VERSION 5.6 ;
BUSBITCHARS "[]" ;
DIVIDERCHAR "/" ;

PROPERTYDEFINITIONS
  PIN DB_Inherited_Net_Expr STRING ;
  LAYER LEF57_SPACING STRING ;
END PROPERTYDEFINITIONS

UNITS
  CAPACITANCE PICOFARADS 1 ;
  DATABASE MICRONS 2000 ;
END UNITS
MANUFACTURINGGRID 0.005 ;
LAYER Oxide
  TYPE MASTERSLICE ;
END Oxide

LAYER Poly
  TYPE MASTERSLICE ;
END Poly

LAYER Nhvt
  TYPE IMPLANT ;
END Nhvt

LAYER Nimp
  TYPE IMPLANT ;
  WIDTH 0.12 ;
  SPACING 0.12 ;
END Nimp

LAYER Phvt
  TYPE IMPLANT ;
END Phvt

LAYER Pimp
  TYPE IMPLANT ;
  WIDTH 0.12 ;
  SPACING 0.12 ;
  SPACING 0 LAYER Nimp ;
END Pimp

LAYER Nzvt
  TYPE IMPLANT ;
  WIDTH 0.35 ;
  SPACING 0.3 ;
END Nzvt

LAYER Nlvt
  TYPE IMPLANT ;
END Nlvt

LAYER Plvt
  TYPE IMPLANT ;
END Plvt

LAYER SiProt
  TYPE IMPLANT ;
  WIDTH 0.22 ;
  SPACING 0.22 ;
END SiProt

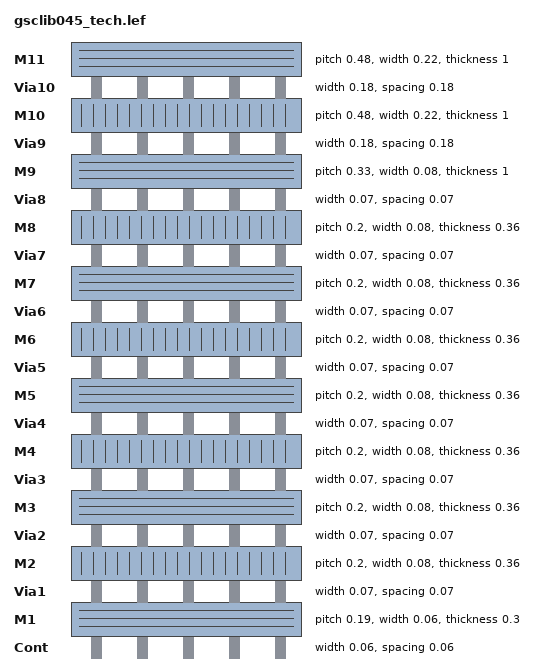
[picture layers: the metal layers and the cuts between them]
LAYER Cont
  TYPE CUT ;
  SPACING 0.06 ;
  SPACING 0.08 ADJACENTCUTS 3 WITHIN 0.1 ;
  WIDTH 0.06 ;
  ENCLOSURE BELOW 0.02 0.03 ;
  ENCLOSURE ABOVE 0 0.03 ;
  ANTENNAMODEL OXIDE1 ;
    ANTENNACUMAREARATIO 1200 ;
  DCCURRENTDENSITY AVERAGE 0.1 ;
END Cont

LAYER M1
  TYPE ROUTING ;
  DIRECTION HORIZONTAL ;
  PITCH 0.19 0.19 ;
  WIDTH 0.06 ;
  AREA 0.02 ;
  SPACINGTABLE
    PARALLELRUNLENGTH 0 0.32 0.75 1.5 2.5 3.5 
    WIDTH 0 0.06 0.06 0.06 0.06 0.06 0.06 
    WIDTH 0.1 0.06 0.1 0.1 0.1 0.1 0.1 
    WIDTH 0.75 0.06 0.1 0.25 0.25 0.25 0.25 
    WIDTH 1.5 0.06 0.1 0.25 0.45 0.45 0.45 
    WIDTH 2.5 0.06 0.1 0.25 0.45 0.75 0.75 
    WIDTH 3.5 0.06 0.1 0.25 0.45 0.75 1.25 ;
  MINENCLOSEDAREA 0.045 ;
  DIAGSPACING 0.08 ;
  DIAGMINEDGELENGTH 0.1 ;
  PROPERTY LEF57_SPACING "SPACING 0.09 ENDOFLINE 0.09 WITHIN 0.025 PARALLELEDGE 0.09 WITHIN 0.025 TWOEDGES ;" ; # OA DATAMODEL 2
  RESISTANCE RPERSQ 0.18 ;
  CAPACITANCE CPERSQDIST 0.0002 ;
  THICKNESS 0.3 ;
  EDGECAPACITANCE 0.0002 ;
  MINIMUMDENSITY 20 ;
  MAXIMUMDENSITY 65 ;
  DENSITYCHECKWINDOW 120 120 ;
  DENSITYCHECKSTEP 60 ;
  ANTENNAMODEL OXIDE1 ;
    ANTENNAAREARATIO 475 ;
  DCCURRENTDENSITY AVERAGE 2 ;
END M1

LAYER Via1
  TYPE CUT ;
  SPACING 0.07 ;
  SPACING 0.1 ADJACENTCUTS 3 WITHIN 0.11 ;
  WIDTH 0.07 ;
  ENCLOSURE BELOW 0.005 0.03 ;
  ENCLOSURE ABOVE 0.005 0.03 ;
  ANTENNAMODEL OXIDE1 ;
    ANTENNAAREARATIO 25 ;
    ANTENNACUMAREARATIO 1200 ;
  DCCURRENTDENSITY AVERAGE 0.1 ;
END Via1

LAYER M2
  TYPE ROUTING ;
  DIRECTION VERTICAL ;
  PITCH 0.2 0.2 ;
  WIDTH 0.08 ;
  AREA 0.02 ;
  SPACINGTABLE
    PARALLELRUNLENGTH 0 0.32 0.75 1.5 2.5 3.5 
    WIDTH 0 0.07 0.07 0.07 0.07 0.07 0.07 
    WIDTH 0.1 0.07 0.15 0.15 0.15 0.15 0.15 
    WIDTH 0.75 0.07 0.15 0.25 0.25 0.25 0.25 
    WIDTH 1.5 0.07 0.15 0.25 0.45 0.45 0.45 
    WIDTH 2.5 0.07 0.15 0.25 0.45 0.75 0.75 
    WIDTH 3.5 0.07 0.15 0.25 0.45 0.75 1.25 ;
  MINENCLOSEDAREA 0.055 ;
  DIAGSPACING 0.1 ;
  DIAGMINEDGELENGTH 0.1 ;
  PROPERTY LEF57_SPACING "SPACING 0.1 ENDOFLINE 0.1 WITHIN 0.035 PARALLELEDGE 0.1 WITHIN 0.035 TWOEDGES ;" ; # OA DATAMODEL 2
  RESISTANCE RPERSQ 0.17 ;
  CAPACITANCE CPERSQDIST 0.0002 ;
  THICKNESS 0.36 ;
  EDGECAPACITANCE 0.0002 ;
  MINIMUMDENSITY 20 ;
  MAXIMUMDENSITY 65 ;
  DENSITYCHECKWINDOW 120 120 ;
  DENSITYCHECKSTEP 60 ;
  ANTENNAMODEL OXIDE1 ;
    ANTENNAAREARATIO 475 ;
  DCCURRENTDENSITY AVERAGE 2 ;
END M2

LAYER Via2
  TYPE CUT ;
  SPACING 0.07 ;
  SPACING 0.1 ADJACENTCUTS 3 WITHIN 0.11 ;
  WIDTH 0.07 ;
  ENCLOSURE BELOW 0.005 0.03 ;
  ENCLOSURE ABOVE 0.005 0.03 ;
  ANTENNAMODEL OXIDE1 ;
    ANTENNAAREARATIO 25 ;
    ANTENNACUMAREARATIO 1200 ;
  DCCURRENTDENSITY AVERAGE 0.1 ;
END Via2

LAYER M3
  TYPE ROUTING ;
  DIRECTION HORIZONTAL ;
  PITCH 0.2 0.2 ;
  WIDTH 0.08 ;
  AREA 0.02 ;
  SPACINGTABLE
    PARALLELRUNLENGTH 0 0.32 0.75 1.5 2.5 3.5 
    WIDTH 0 0.07 0.07 0.07 0.07 0.07 0.07 
    WIDTH 0.1 0.07 0.15 0.15 0.15 0.15 0.15 
    WIDTH 0.75 0.07 0.15 0.25 0.25 0.25 0.25 
    WIDTH 1.5 0.07 0.15 0.25 0.45 0.45 0.45 
    WIDTH 2.5 0.07 0.15 0.25 0.45 0.75 0.75 
    WIDTH 3.5 0.07 0.15 0.25 0.45 0.75 1.25 ;
  MINENCLOSEDAREA 0.055 ;
  DIAGSPACING 0.1 ;
  DIAGMINEDGELENGTH 0.1 ;
  PROPERTY LEF57_SPACING "SPACING 0.1 ENDOFLINE 0.1 WITHIN 0.035 PARALLELEDGE 0.1 WITHIN 0.035 TWOEDGES ;" ; # OA DATAMODEL 2
  RESISTANCE RPERSQ 0.17 ;
  CAPACITANCE CPERSQDIST 0.0002 ;
  THICKNESS 0.36 ;
  EDGECAPACITANCE 0.0002 ;
  MINIMUMDENSITY 20 ;
  MAXIMUMDENSITY 65 ;
  DENSITYCHECKWINDOW 120 120 ;
  DENSITYCHECKSTEP 60 ;
  ANTENNAMODEL OXIDE1 ;
    ANTENNAAREARATIO 475 ;
  DCCURRENTDENSITY AVERAGE 2 ;
END M3

LAYER Via3
  TYPE CUT ;
  SPACING 0.07 ;
  SPACING 0.1 ADJACENTCUTS 3 WITHIN 0.11 ;
  WIDTH 0.07 ;
  ENCLOSURE BELOW 0.005 0.03 ;
  ENCLOSURE ABOVE 0.005 0.03 ;
  ANTENNAMODEL OXIDE1 ;
    ANTENNAAREARATIO 25 ;
    ANTENNACUMAREARATIO 1200 ;
  DCCURRENTDENSITY AVERAGE 0.1 ;
END Via3

LAYER M4
  TYPE ROUTING ;
  DIRECTION VERTICAL ;
  PITCH 0.2 0.2 ;
  WIDTH 0.08 ;
  AREA 0.02 ;
  SPACINGTABLE
    PARALLELRUNLENGTH 0 0.32 0.75 1.5 2.5 3.5 
    WIDTH 0 0.07 0.07 0.07 0.07 0.07 0.07 
    WIDTH 0.1 0.07 0.15 0.15 0.15 0.15 0.15 
    WIDTH 0.75 0.07 0.15 0.25 0.25 0.25 0.25 
    WIDTH 1.5 0.07 0.15 0.25 0.45 0.45 0.45 
    WIDTH 2.5 0.07 0.15 0.25 0.45 0.75 0.75 
    WIDTH 3.5 0.07 0.15 0.25 0.45 0.75 1.25 ;
  MINENCLOSEDAREA 0.055 ;
  DIAGSPACING 0.1 ;
  DIAGMINEDGELENGTH 0.1 ;
  PROPERTY LEF57_SPACING "SPACING 0.1 ENDOFLINE 0.1 WITHIN 0.035 PARALLELEDGE 0.1 WITHIN 0.035 TWOEDGES ;" ; # OA DATAMODEL 2
  RESISTANCE RPERSQ 0.17 ;
  CAPACITANCE CPERSQDIST 0.0002 ;
  THICKNESS 0.36 ;
  EDGECAPACITANCE 0.0002 ;
  MINIMUMDENSITY 20 ;
  MAXIMUMDENSITY 65 ;
  DENSITYCHECKWINDOW 120 120 ;
  DENSITYCHECKSTEP 60 ;
  ANTENNAMODEL OXIDE1 ;
    ANTENNAAREARATIO 475 ;
  DCCURRENTDENSITY AVERAGE 2 ;
END M4

LAYER Via4
  TYPE CUT ;
  SPACING 0.07 ;
  SPACING 0.1 ADJACENTCUTS 3 WITHIN 0.11 ;
  WIDTH 0.07 ;
  ENCLOSURE BELOW 0.005 0.03 ;
  ENCLOSURE ABOVE 0.005 0.03 ;
  ANTENNAMODEL OXIDE1 ;
    ANTENNAAREARATIO 25 ;
    ANTENNACUMAREARATIO 1200 ;
  DCCURRENTDENSITY AVERAGE 0.1 ;
END Via4

LAYER M5
  TYPE ROUTING ;
  DIRECTION HORIZONTAL ;
  PITCH 0.2 0.2 ;
  WIDTH 0.08 ;
  AREA 0.02 ;
  SPACINGTABLE
    PARALLELRUNLENGTH 0 0.32 0.75 1.5 2.5 3.5 
    WIDTH 0 0.07 0.07 0.07 0.07 0.07 0.07 
    WIDTH 0.1 0.07 0.15 0.15 0.15 0.15 0.15 
    WIDTH 0.75 0.07 0.15 0.25 0.25 0.25 0.25 
    WIDTH 1.5 0.07 0.15 0.25 0.45 0.45 0.45 
    WIDTH 2.5 0.07 0.15 0.25 0.45 0.75 0.75 
    WIDTH 3.5 0.07 0.15 0.25 0.45 0.75 1.25 ;
  MINENCLOSEDAREA 0.055 ;
  DIAGSPACING 0.1 ;
  DIAGMINEDGELENGTH 0.1 ;
  PROPERTY LEF57_SPACING "SPACING 0.1 ENDOFLINE 0.1 WITHIN 0.035 PARALLELEDGE 0.1 WITHIN 0.035 TWOEDGES ;" ; # OA DATAMODEL 2
  RESISTANCE RPERSQ 0.17 ;
  CAPACITANCE CPERSQDIST 0.0002 ;
  THICKNESS 0.36 ;
  EDGECAPACITANCE 0.0002 ;
  MINIMUMDENSITY 20 ;
  MAXIMUMDENSITY 65 ;
  DENSITYCHECKWINDOW 120 120 ;
  DENSITYCHECKSTEP 60 ;
  ANTENNAMODEL OXIDE1 ;
    ANTENNAAREARATIO 475 ;
  DCCURRENTDENSITY AVERAGE 2 ;
END M5

LAYER Via5
  TYPE CUT ;
  SPACING 0.07 ;
  SPACING 0.1 ADJACENTCUTS 3 WITHIN 0.11 ;
  WIDTH 0.07 ;
  ENCLOSURE BELOW 0.005 0.03 ;
  ENCLOSURE ABOVE 0.005 0.03 ;
  ANTENNAMODEL OXIDE1 ;
    ANTENNAAREARATIO 25 ;
    ANTENNACUMAREARATIO 1200 ;
  DCCURRENTDENSITY AVERAGE 0.1 ;
END Via5

LAYER M6
  TYPE ROUTING ;
  DIRECTION VERTICAL ;
  PITCH 0.2 0.2 ;
  WIDTH 0.08 ;
  AREA 0.02 ;
  SPACINGTABLE
    PARALLELRUNLENGTH 0 0.32 0.75 1.5 2.5 3.5 
    WIDTH 0 0.07 0.07 0.07 0.07 0.07 0.07 
    WIDTH 0.1 0.07 0.15 0.15 0.15 0.15 0.15 
    WIDTH 0.75 0.07 0.15 0.25 0.25 0.25 0.25 
    WIDTH 1.5 0.07 0.15 0.25 0.45 0.45 0.45 
    WIDTH 2.5 0.07 0.15 0.25 0.45 0.75 0.75 
    WIDTH 3.5 0.07 0.15 0.25 0.45 0.75 1.25 ;
  MINENCLOSEDAREA 0.055 ;
  DIAGSPACING 0.1 ;
  DIAGMINEDGELENGTH 0.1 ;
  PROPERTY LEF57_SPACING "SPACING 0.1 ENDOFLINE 0.1 WITHIN 0.035 PARALLELEDGE 0.1 WITHIN 0.035 TWOEDGES ;" ; # OA DATAMODEL 2
  RESISTANCE RPERSQ 0.17 ;
  CAPACITANCE CPERSQDIST 0.0002 ;
  THICKNESS 0.36 ;
  EDGECAPACITANCE 0.0002 ;
  MINIMUMDENSITY 20 ;
  MAXIMUMDENSITY 65 ;
  DENSITYCHECKWINDOW 120 120 ;
  DENSITYCHECKSTEP 60 ;
  ANTENNAMODEL OXIDE1 ;
    ANTENNAAREARATIO 475 ;
  DCCURRENTDENSITY AVERAGE 2 ;
END M6

LAYER Via6
  TYPE CUT ;
  SPACING 0.07 ;
  SPACING 0.1 ADJACENTCUTS 3 WITHIN 0.11 ;
  WIDTH 0.07 ;
  ENCLOSURE BELOW 0.005 0.03 ;
  ENCLOSURE ABOVE 0.005 0.03 ;
  ANTENNAMODEL OXIDE1 ;
    ANTENNAAREARATIO 25 ;
    ANTENNACUMAREARATIO 1200 ;
  DCCURRENTDENSITY AVERAGE 0.1 ;
END Via6

LAYER M7
  TYPE ROUTING ;
  DIRECTION HORIZONTAL ;
  PITCH 0.2 0.2 ;
  WIDTH 0.08 ;
  AREA 0.02 ;
  SPACINGTABLE
    PARALLELRUNLENGTH 0 0.32 0.75 1.5 2.5 3.5 
    WIDTH 0 0.07 0.07 0.07 0.07 0.07 0.07 
    WIDTH 0.1 0.07 0.15 0.15 0.15 0.15 0.15 
    WIDTH 0.75 0.07 0.15 0.25 0.25 0.25 0.25 
    WIDTH 1.5 0.07 0.15 0.25 0.45 0.45 0.45 
    WIDTH 2.5 0.07 0.15 0.25 0.45 0.75 0.75 
    WIDTH 3.5 0.07 0.15 0.25 0.45 0.75 1.25 ;
  MINENCLOSEDAREA 0.055 ;
  DIAGSPACING 0.1 ;
  DIAGMINEDGELENGTH 0.1 ;
  PROPERTY LEF57_SPACING "SPACING 0.1 ENDOFLINE 0.1 WITHIN 0.035 PARALLELEDGE 0.1 WITHIN 0.035 TWOEDGES ;" ; # OA DATAMODEL 2
  RESISTANCE RPERSQ 0.17 ;
  CAPACITANCE CPERSQDIST 0.0002 ;
  THICKNESS 0.36 ;
  EDGECAPACITANCE 0.0002 ;
  MINIMUMDENSITY 20 ;
  MAXIMUMDENSITY 65 ;
  DENSITYCHECKWINDOW 120 120 ;
  DENSITYCHECKSTEP 60 ;
  ANTENNAMODEL OXIDE1 ;
    ANTENNAAREARATIO 475 ;
  DCCURRENTDENSITY AVERAGE 2 ;
END M7

LAYER Via7
  TYPE CUT ;
  SPACING 0.07 ;
  SPACING 0.1 ADJACENTCUTS 3 WITHIN 0.11 ;
  WIDTH 0.07 ;
  ENCLOSURE BELOW 0.005 0.03 ;
  ENCLOSURE ABOVE 0.005 0.03 ;
  ANTENNAMODEL OXIDE1 ;
    ANTENNAAREARATIO 25 ;
    ANTENNACUMAREARATIO 1200 ;
  DCCURRENTDENSITY AVERAGE 0.1 ;
END Via7

LAYER M8
  TYPE ROUTING ;
  DIRECTION VERTICAL ;
  PITCH 0.2 0.2 ;
  WIDTH 0.08 ;
  AREA 0.02 ;
  SPACINGTABLE
    PARALLELRUNLENGTH 0 0.32 0.75 1.5 2.5 3.5 
    WIDTH 0 0.07 0.07 0.07 0.07 0.07 0.07 
    WIDTH 0.1 0.07 0.15 0.15 0.15 0.15 0.15 
    WIDTH 0.75 0.07 0.15 0.25 0.25 0.25 0.25 
    WIDTH 1.5 0.07 0.15 0.25 0.45 0.45 0.45 
    WIDTH 2.5 0.07 0.15 0.25 0.45 0.75 0.75 
    WIDTH 3.5 0.07 0.15 0.25 0.45 0.75 1.25 ;
  MINENCLOSEDAREA 0.055 ;
  DIAGSPACING 0.1 ;
  DIAGMINEDGELENGTH 0.1 ;
  PROPERTY LEF57_SPACING "SPACING 0.1 ENDOFLINE 0.1 WITHIN 0.035 PARALLELEDGE 0.1 WITHIN 0.035 TWOEDGES ;" ; # OA DATAMODEL 2
  RESISTANCE RPERSQ 0.17 ;
  CAPACITANCE CPERSQDIST 0.0002 ;
  THICKNESS 0.36 ;
  EDGECAPACITANCE 0.0002 ;
  MINIMUMDENSITY 20 ;
  MAXIMUMDENSITY 65 ;
  DENSITYCHECKWINDOW 120 120 ;
  DENSITYCHECKSTEP 60 ;
  ANTENNAMODEL OXIDE1 ;
    ANTENNAAREARATIO 475 ;
  DCCURRENTDENSITY AVERAGE 2 ;
END M8

LAYER Via8
  TYPE CUT ;
  SPACING 0.07 ;
  SPACING 0.1 ADJACENTCUTS 3 WITHIN 0.11 ;
  WIDTH 0.07 ;
  ENCLOSURE BELOW 0.005 0.03 ;
  ENCLOSURE ABOVE 0.005 0.03 ;
  ANTENNAMODEL OXIDE1 ;
    ANTENNAAREARATIO 25 ;
    ANTENNACUMAREARATIO 1200 ;
  DCCURRENTDENSITY AVERAGE 0.1 ;
END Via8

LAYER M9
  TYPE ROUTING ;
  DIRECTION HORIZONTAL ;
  PITCH 0.33 0.33 ;
  WIDTH 0.08 ;
  AREA 0.02 ;
  SPACINGTABLE
    PARALLELRUNLENGTH 0 0.32 0.75 1.5 2.5 3.5 
    WIDTH 0 0.07 0.07 0.07 0.07 0.07 0.07 
    WIDTH 0.1 0.07 0.15 0.15 0.15 0.15 0.15 
    WIDTH 0.75 0.07 0.15 0.25 0.25 0.25 0.25 
    WIDTH 1.5 0.07 0.15 0.25 0.45 0.45 0.45 
    WIDTH 2.5 0.07 0.15 0.25 0.45 0.75 0.75 
    WIDTH 3.5 0.07 0.15 0.25 0.45 0.75 1.25 ;
  MINENCLOSEDAREA 0.055 ;
  DIAGSPACING 0.1 ;
  DIAGMINEDGELENGTH 0.1 ;
  PROPERTY LEF57_SPACING "SPACING 0.1 ENDOFLINE 0.1 WITHIN 0.035 PARALLELEDGE 0.1 WITHIN 0.035 TWOEDGES ;" ; # OA DATAMODEL 2
  RESISTANCE RPERSQ 0.02 ;
  CAPACITANCE CPERSQDIST 0.0002 ;
  THICKNESS 1 ;
  EDGECAPACITANCE 0.0002 ;
  MINIMUMDENSITY 20 ;
  MAXIMUMDENSITY 65 ;
  DENSITYCHECKWINDOW 120 120 ;
  DENSITYCHECKSTEP 60 ;
  ANTENNAMODEL OXIDE1 ;
    ANTENNAAREARATIO 475 ;
  DCCURRENTDENSITY AVERAGE 2 ;
END M9

LAYER Via9
  TYPE CUT ;
  SPACING 0.18 ;
  SPACING 0.2 ADJACENTCUTS 3 WITHIN 0.25 ;
  WIDTH 0.18 ;
  ENCLOSURE BELOW 0.015 0.04 ;
  ENCLOSURE ABOVE 0.03 0.05 ;
  ANTENNAMODEL OXIDE1 ;
    ANTENNAAREARATIO 25 ;
    ANTENNACUMAREARATIO 1200 ;
  DCCURRENTDENSITY AVERAGE 0.8 ;
END Via9

LAYER M10
  TYPE ROUTING ;
  DIRECTION VERTICAL ;
  PITCH 0.48 0.48 ;
  WIDTH 0.22 ;
  AREA 0.1 ;
  SPACINGTABLE
    PARALLELRUNLENGTH 0 0.75 1.5 2.5 3.5 
    WIDTH 0 0.2 0.2 0.2 0.2 0.2 
    WIDTH 0.75 0.2 0.35 0.45 0.75 1.25 
    WIDTH 1.5 0.2 0.35 0.45 0.45 0.45 
    WIDTH 2.5 0.2 0.35 0.45 0.75 0.75 
    WIDTH 3.5 0.2 0.35 0.45 0.75 1.25 ;
  MINENCLOSEDAREA 0.11 ;
  RESISTANCE RPERSQ 0.02 ;
  CAPACITANCE CPERSQDIST 0.0002 ;
  THICKNESS 1 ;
  EDGECAPACITANCE 0.0002 ;
  MINIMUMDENSITY 20 ;
  MAXIMUMDENSITY 65 ;
  DENSITYCHECKWINDOW 120 120 ;
  DENSITYCHECKSTEP 60 ;
  ANTENNAMODEL OXIDE1 ;
    ANTENNAAREARATIO 475 ;
  DCCURRENTDENSITY AVERAGE 8 ;
END M10

LAYER Via10
  TYPE CUT ;
  SPACING 0.18 ;
  SPACING 0.2 ADJACENTCUTS 3 WITHIN 0.25 ;
  WIDTH 0.18 ;
  ENCLOSURE BELOW 0.015 0.04 ;
  ENCLOSURE ABOVE 0.03 0.05 ;
  ANTENNAMODEL OXIDE1 ;
    ANTENNAAREARATIO 25 ;
    ANTENNACUMAREARATIO 1200 ;
  DCCURRENTDENSITY AVERAGE 0.8 ;
END Via10

LAYER M11
  TYPE ROUTING ;
  DIRECTION HORIZONTAL ;
  PITCH 0.48 0.48 ;
  WIDTH 0.22 ;
  AREA 0.1 ;
  SPACINGTABLE
    PARALLELRUNLENGTH 0 0.75 1.5 2.5 3.5 
    WIDTH 0 0.2 0.2 0.2 0.2 0.2 
    WIDTH 0.75 0.2 0.35 0.45 0.75 1.25 
    WIDTH 1.5 0.2 0.35 0.45 0.45 0.45 
    WIDTH 2.5 0.2 0.35 0.45 0.75 0.75 
    WIDTH 3.5 0.2 0.35 0.45 0.75 1.25 ;
  MINENCLOSEDAREA 0.11 ;
  RESISTANCE RPERSQ 0.02 ;
  CAPACITANCE CPERSQDIST 0.0002 ;
  THICKNESS 1 ;
  EDGECAPACITANCE 0.0002 ;
  MINIMUMDENSITY 20 ;
  MAXIMUMDENSITY 65 ;
  DENSITYCHECKWINDOW 120 120 ;
  DENSITYCHECKSTEP 60 ;
  ANTENNAMODEL OXIDE1 ;
    ANTENNAAREARATIO 475 ;
  DCCURRENTDENSITY AVERAGE 8 ;
END M11

LAYER OVERLAP
  TYPE OVERLAP ;
END OVERLAP

MAXVIASTACK 4 RANGE M1 M9 ;
VIARULE M11_M10 GENERATE DEFAULT
  LAYER M10 ;
    ENCLOSURE 0.015 0.04 ;
  LAYER M11 ;
    ENCLOSURE 0.03 0.05 ;
  LAYER Via10 ;
    RECT -0.09 -0.09 0.09 0.09 ;
    SPACING 0.36 BY 0.36 ;
    RESISTANCE 0.040000 ;
END M11_M10

VIARULE M10_M9 GENERATE DEFAULT
  LAYER M9 ;
    ENCLOSURE 0.015 0.04 ;
  LAYER M10 ;
    ENCLOSURE 0.03 0.05 ;
  LAYER Via9 ;
    RECT -0.09 -0.09 0.09 0.09 ;
    SPACING 0.36 BY 0.36 ;
    RESISTANCE 0.200000 ;
END M10_M9

VIARULE M9_M8 GENERATE DEFAULT
  LAYER M8 ;
    ENCLOSURE 0.005 0.03 ;
  LAYER M9 ;
    ENCLOSURE 0.005 0.03 ;
  LAYER Via8 ;
    RECT -0.035 -0.035 0.035 0.035 ;
    SPACING 0.14 BY 0.14 ;
    RESISTANCE 0.200000 ;
END M9_M8

VIARULE M8_M7 GENERATE DEFAULT
  LAYER M7 ;
    ENCLOSURE 0.005 0.03 ;
  LAYER M8 ;
    ENCLOSURE 0.005 0.03 ;
  LAYER Via7 ;
    RECT -0.035 -0.035 0.035 0.035 ;
    SPACING 0.14 BY 0.14 ;
    RESISTANCE 5.000000 ;
END M8_M7

VIARULE M7_M6 GENERATE DEFAULT
  LAYER M6 ;
    ENCLOSURE 0.005 0.03 ;
  LAYER M7 ;
    ENCLOSURE 0.005 0.03 ;
  LAYER Via6 ;
    RECT -0.035 -0.035 0.035 0.035 ;
    SPACING 0.14 BY 0.14 ;
    RESISTANCE 5.000000 ;
END M7_M6

VIARULE M6_M5 GENERATE DEFAULT
  LAYER M5 ;
    ENCLOSURE 0.005 0.03 ;
  LAYER M6 ;
    ENCLOSURE 0.005 0.03 ;
  LAYER Via5 ;
    RECT -0.035 -0.035 0.035 0.035 ;
    SPACING 0.14 BY 0.14 ;
    RESISTANCE 5.000000 ;
END M6_M5

VIARULE M5_M4 GENERATE DEFAULT
  LAYER M4 ;
    ENCLOSURE 0.005 0.03 ;
  LAYER M5 ;
    ENCLOSURE 0.005 0.03 ;
  LAYER Via4 ;
    RECT -0.035 -0.035 0.035 0.035 ;
    SPACING 0.14 BY 0.14 ;
    RESISTANCE 5.000000 ;
END M5_M4

VIARULE M4_M3 GENERATE DEFAULT
  LAYER M3 ;
    ENCLOSURE 0.005 0.03 ;
  LAYER M4 ;
    ENCLOSURE 0.005 0.03 ;
  LAYER Via3 ;
    RECT -0.035 -0.035 0.035 0.035 ;
    SPACING 0.14 BY 0.14 ;
    RESISTANCE 5.000000 ;
END M4_M3

VIARULE M3_M2 GENERATE DEFAULT
  LAYER M2 ;
    ENCLOSURE 0.005 0.03 ;
  LAYER M3 ;
    ENCLOSURE 0.005 0.03 ;
  LAYER Via2 ;
    RECT -0.035 -0.035 0.035 0.035 ;
    SPACING 0.14 BY 0.14 ;
    RESISTANCE 5.000000 ;
END M3_M2

VIARULE M2_M1 GENERATE DEFAULT
  LAYER M1 ;
    ENCLOSURE 0.005 0.03 ;
  LAYER M2 ;
    ENCLOSURE 0.005 0.03 ;
  LAYER Via1 ;
    RECT -0.035 -0.035 0.035 0.035 ;
    SPACING 0.14 BY 0.14 ;
    RESISTANCE 5.000000 ;
END M2_M1

VIARULE M1_PO GENERATE
  LAYER Poly ;
    ENCLOSURE 0.02 0.03 ;
  LAYER M1 ;
    ENCLOSURE 0 0.03 ;
  LAYER Cont ;
    RECT -0.03 -0.03 0.03 0.03 ;
    SPACING 0.12 BY 0.12 ;
    RESISTANCE 41.000000 ;
END M1_PO

VIARULE M1_DIFF GENERATE
  LAYER Oxide ;
    ENCLOSURE 0.03 0.03 ;
  LAYER M1 ;
    ENCLOSURE 0 0.03 ;
  LAYER Cont ;
    RECT -0.03 -0.03 0.03 0.03 ;
    SPACING 0.12 BY 0.12 ;
    RESISTANCE 56.000000 ;
END M1_DIFF

VIARULE M1_PSUB GENERATE
  LAYER Oxide ;
    ENCLOSURE 0.03 0.03 ;
  LAYER M1 ;
    ENCLOSURE 0 0.03 ;
  LAYER Cont ;
    RECT -0.03 -0.03 0.03 0.03 ;
    SPACING 0.12 BY 0.12 ;
    RESISTANCE 56.000000 ;
END M1_PSUB

VIARULE M1_PIMP GENERATE
  LAYER Oxide ;
    ENCLOSURE 0.03 0.03 ;
  LAYER M1 ;
    ENCLOSURE 0 0.03 ;
  LAYER Cont ;
    RECT -0.03 -0.03 0.03 0.03 ;
    SPACING 0.12 BY 0.12 ;
    RESISTANCE 56.000000 ;
END M1_PIMP

VIARULE M1_NIMP GENERATE
  LAYER Oxide ;
    ENCLOSURE 0.03 0.03 ;
  LAYER M1 ;
    ENCLOSURE 0 0.03 ;
  LAYER Cont ;
    RECT -0.03 -0.03 0.03 0.03 ;
    SPACING 0.12 BY 0.12 ;
    RESISTANCE 56.000000 ;
END M1_NIMP

VIARULE M1_NWELL GENERATE
  LAYER Oxide ;
    ENCLOSURE 0.03 0.03 ;
  LAYER M1 ;
    ENCLOSURE 0 0.03 ;
  LAYER Cont ;
    RECT -0.03 -0.03 0.03 0.03 ;
    SPACING 0.12 BY 0.12 ;
    RESISTANCE 56.000000 ;
END M1_NWELL

NONDEFAULTRULE VLMDefaultSetup
  LAYER M1
    WIDTH 0.06 ;
  END M1
  LAYER M2
    WIDTH 0.08 ;
  END M2
  LAYER M3
    WIDTH 0.08 ;
  END M3
  LAYER M4
    WIDTH 0.08 ;
  END M4
  LAYER M5
    WIDTH 0.08 ;
  END M5
  LAYER M6
    WIDTH 0.08 ;
  END M6
  LAYER M7
    WIDTH 0.08 ;
  END M7
  LAYER M8
    WIDTH 0.08 ;
  END M8
  LAYER M9
    WIDTH 0.08 ;
  END M9
  LAYER M10
    WIDTH 0.22 ;
  END M10
  LAYER M11
    WIDTH 0.22 ;
  END M11
  USEVIARULE M1_PO ;
  USEVIARULE M1_NWELL ;
  USEVIARULE M1_PSUB ;
  USEVIARULE M1_NIMP ;
  USEVIARULE M1_PIMP ;
  USEVIARULE M1_DIFF ;
  USEVIARULE M2_M1 ;
  USEVIARULE M3_M2 ;
  USEVIARULE M4_M3 ;
  USEVIARULE M5_M4 ;
  USEVIARULE M6_M5 ;
  USEVIARULE M7_M6 ;
  USEVIARULE M8_M7 ;
  USEVIARULE M9_M8 ;
  USEVIARULE M10_M9 ;
  USEVIARULE M11_M10 ;
END VLMDefaultSetup
SITE CoreSite
  CLASS CORE ;
  SIZE 0.2 BY 1.71 ;
END CoreSite

END LIBRARY
